VERSION 5.7 ;
  NOWIREEXTENSIONATPIN ON ;
  DIVIDERCHAR "/" ;
  BUSBITCHARS "[]" ;
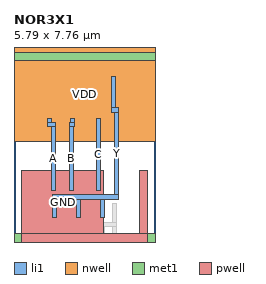
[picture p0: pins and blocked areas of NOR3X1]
MACRO NOR3X1
  CLASS CORE ;
  FOREIGN NOR3X1 ;
  ORIGIN 0.000 0.000 ;
  SIZE 5.790 BY 7.760 ;
  SYMMETRY X Y ;
  SITE unitrh ;
  PIN Y
    DIRECTION OUTPUT ;
    USE SIGNAL ;
    ANTENNADIFFAREA 1.154200 ;
    PORT
      LAYER li1 ;
        RECT 3.995 5.475 4.165 6.745 ;
        RECT 3.995 5.305 4.275 5.475 ;
        RECT 4.105 1.920 4.275 5.305 ;
        RECT 1.585 1.750 4.275 1.920 ;
        RECT 1.585 1.015 1.755 1.750 ;
        RECT 2.555 1.015 2.725 1.750 ;
        RECT 3.525 1.015 3.695 1.750 ;
    END
  END Y
  PIN A
    DIRECTION INPUT ;
    USE SIGNAL ;
    ANTENNAGATEAREA 1.027250 ;
    PORT
      LAYER li1 ;
        RECT 1.360 4.890 1.530 5.050 ;
        RECT 1.360 4.720 1.685 4.890 ;
        RECT 1.515 2.095 1.685 4.720 ;
    END
  END A
  PIN B
    DIRECTION INPUT ;
    USE SIGNAL ;
    ANTENNAGATEAREA 1.026450 ;
    PORT
      LAYER li1 ;
        RECT 2.290 4.890 2.460 5.050 ;
        RECT 2.255 4.720 2.460 4.890 ;
        RECT 2.255 2.095 2.425 4.720 ;
    END
  END B
  PIN C
    DIRECTION INPUT ;
    USE SIGNAL ;
    ANTENNAGATEAREA 1.026450 ;
    PORT
      LAYER li1 ;
        RECT 3.365 2.095 3.535 5.050 ;
    END
  END C
  PIN VDD
    DIRECTION INOUT ;
    USE POWER ;
    SHAPE ABUTMENT ;
    PORT
      LAYER nwell ;
        RECT 0.000 4.110 5.790 7.940 ;
      LAYER met1 ;
        RECT 0.000 7.410 5.790 7.760 ;
    END
  END VDD
  PIN GND
    DIRECTION INOUT ;
    USE POWER ;
    SHAPE ABUTMENT ;
    PORT
      LAYER pwell ;
        RECT 0.320 0.350 3.650 2.900 ;
        RECT 5.130 0.350 5.470 2.900 ;
        RECT 0.320 0.000 5.470 0.350 ;
      LAYER met1 ;
        RECT 0.000 0.000 5.790 0.350 ;
    END
  END GND
  OBS
      LAYER li1 ;
        RECT 0.000 7.410 5.790 7.760 ;
        RECT 0.320 4.290 0.660 7.410 ;
        RECT 1.195 5.475 1.365 7.205 ;
        RECT 1.635 5.735 1.805 7.410 ;
        RECT 2.075 7.005 3.125 7.175 ;
        RECT 2.075 5.475 2.245 7.005 ;
        RECT 1.195 5.305 2.245 5.475 ;
        RECT 2.515 5.475 2.685 6.745 ;
        RECT 2.955 5.735 3.125 7.005 ;
        RECT 3.555 7.005 4.605 7.175 ;
        RECT 3.555 5.475 3.725 7.005 ;
        RECT 4.435 5.735 4.605 7.005 ;
        RECT 2.515 5.305 3.725 5.475 ;
        RECT 5.130 4.290 5.470 7.410 ;
        RECT 0.320 0.350 0.660 2.900 ;
        RECT 1.100 0.795 1.270 1.925 ;
        RECT 2.070 0.795 2.240 1.570 ;
        RECT 3.040 0.795 3.210 1.570 ;
        RECT 4.010 0.795 4.180 1.570 ;
        RECT 1.100 0.625 4.180 0.795 ;
        RECT 1.100 0.350 1.270 0.625 ;
        RECT 1.585 0.350 1.755 0.625 ;
        RECT 2.070 0.350 2.240 0.625 ;
        RECT 2.555 0.350 2.725 0.625 ;
        RECT 3.040 0.350 3.210 0.625 ;
        RECT 3.525 0.350 3.695 0.625 ;
        RECT 4.010 0.350 4.180 0.625 ;
        RECT 5.130 0.350 5.470 2.900 ;
        RECT 0.000 0.000 5.790 0.350 ;
      LAYER mcon ;
        RECT 0.775 7.495 0.945 7.665 ;
        RECT 1.145 7.495 1.315 7.665 ;
        RECT 1.515 7.495 1.685 7.665 ;
        RECT 1.885 7.495 2.055 7.665 ;
        RECT 2.255 7.495 2.425 7.665 ;
        RECT 2.625 7.495 2.795 7.665 ;
        RECT 2.995 7.495 3.165 7.665 ;
        RECT 3.365 7.495 3.535 7.665 ;
        RECT 3.735 7.495 3.905 7.665 ;
        RECT 4.105 7.495 4.275 7.665 ;
        RECT 4.475 7.495 4.645 7.665 ;
        RECT 4.845 7.495 5.015 7.665 ;
        RECT 0.775 0.095 0.945 0.265 ;
        RECT 1.145 0.095 1.315 0.265 ;
        RECT 1.515 0.095 1.685 0.265 ;
        RECT 1.885 0.095 2.055 0.265 ;
        RECT 2.255 0.095 2.425 0.265 ;
        RECT 2.625 0.095 2.795 0.265 ;
        RECT 2.995 0.095 3.165 0.265 ;
        RECT 3.365 0.095 3.535 0.265 ;
        RECT 3.735 0.095 3.905 0.265 ;
        RECT 4.105 0.095 4.275 0.265 ;
        RECT 4.475 0.095 4.645 0.265 ;
        RECT 4.845 0.095 5.015 0.265 ;
  END
END NOR3X1
END LIBRARY

